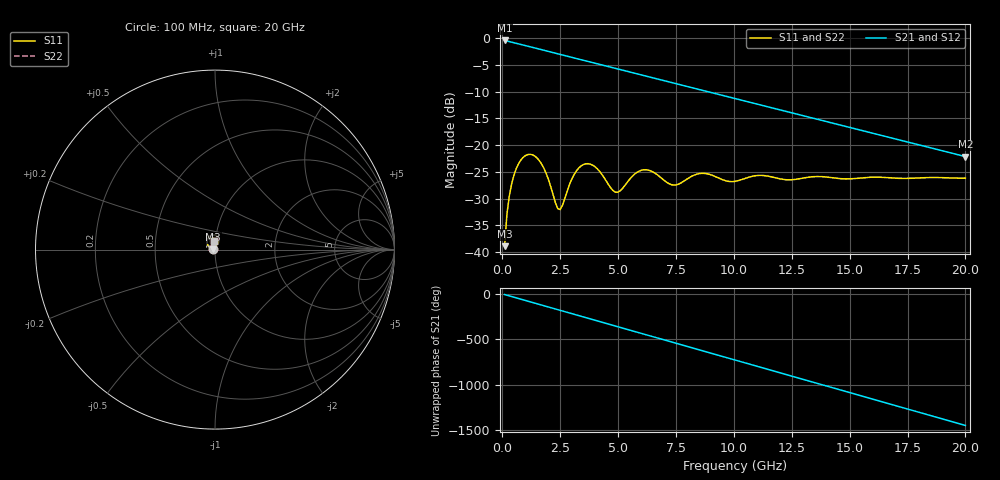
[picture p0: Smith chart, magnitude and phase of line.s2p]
# Hz S RI R 50.0
!freq ReS11 ImS11 ReS21 ImS21 ReS12 ImS12 ReS22 ImS22
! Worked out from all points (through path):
!   200 points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, 100 MHz to 20 GHz, reference 50 ohm
!   highest |S21| = -0.47 dB at 100 MHz (marker M1); lowest = -22.1 dB at 20 GHz (marker M2)
!   group delay of S21, straight-line fit = 201 ps
!   lowest |S11| = -38.9 dB at 100 MHz (marker M3), VSWR 1.02, Z = 48.9 + j0.187 ohm
!   |S11| at or under -10 dB: start of sweep to end of sweep
!   |S22| runs from -38.9 to -21.7 dB; largest |S21 - S12| = 1.7e-15
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1e8  -0.0112 0.00191  0.94 -0.1194  0.94 -0.1194  -0.0112 0.00191
3e8  -0.0307 0.0127  0.8588 -0.3414  0.8588 -0.3414  -0.0307 0.0127
5e8  -0.0422 0.0306  0.7283 -0.5318  0.7283 -0.5318  -0.0422 0.0306
1.3e9  -0.00439 0.081  -0.0597 -0.8153  -0.0597 -0.8153  -0.00439 0.081
1.9e9  0.0228 0.0491  -0.5602 -0.5091  -0.5602 -0.5091  0.0228 0.0491
2.4e9  0.00259 0.0253  -0.7059 -0.0753  -0.7059 -0.0753  0.00259 0.0253
3.5e9  -0.0168 0.0636  -0.1757 0.5939  -0.1757 0.5939  -0.0168 0.0636
4.1e9  0.00713 0.0597  0.2611 0.5116  0.2611 0.5116  0.00713 0.0597
4.9e9  -0.00132 0.0363  0.5169 0.0455  0.5169 0.0455  -0.00132 0.0363
5.9e9  -0.0129 0.0556  0.1764 -0.4227  0.1764 -0.4227  -0.0129 0.0556
6.8e9  0.00321 0.0506  -0.2768 -0.3012  -0.2768 -0.3012  0.00321 0.0506
7.6e9  -0.00666 0.0426  -0.3636 0.0674  -0.3636 0.0674  -0.00666 0.0426
8.5e9  -0.0079 0.0536  -0.0818 0.3202  -0.0818 0.3202  -0.0079 0.0536
9.4e9  -0.000592 0.0487  0.229 0.1863  0.229 0.1863  -0.000592 0.0487
1.01e10  -0.00594 0.0457  0.2648 -0.0541  0.2648 -0.0541  -0.00594 0.0457
1.11e10  -0.0057 0.0518  0.0251 -0.2372  0.0251 -0.2372  -0.0057 0.0518
1.21e10  -0.00311 0.0478  -0.1928 -0.0843  -0.1928 -0.0843  -0.00311 0.0478
1.34e10  -0.00595 0.0503  -0.0596 0.1685  -0.0596 0.1685  -0.00595 0.0503
1.49e10  -0.00471 0.0481  0.1481 0.00218  0.1481 0.00218  -0.00471 0.0481
1.67e10  -0.00418 0.0494  -0.0752 -0.0912  -0.0752 -0.0912  -0.00418 0.0494
1.84e10  -0.00513 0.0496  -0.0285 0.0911  -0.0285 0.0911  -0.00513 0.0496
2e10  -0.0049 0.0489  0.0773 -0.0115  0.0773 -0.0115  -0.0049 0.0489
